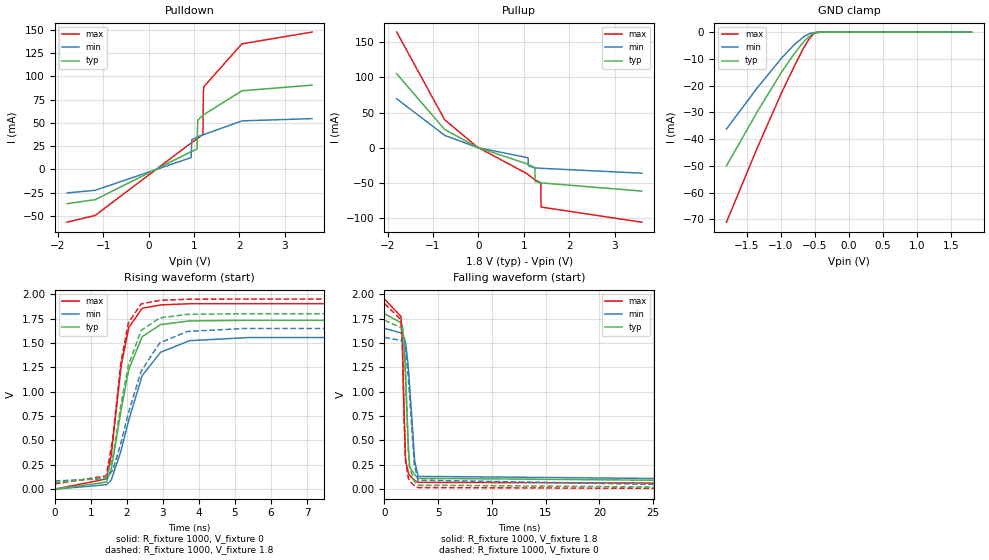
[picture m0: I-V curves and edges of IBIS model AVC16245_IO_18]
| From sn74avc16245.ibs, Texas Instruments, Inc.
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[Model]   AVC16245_IO_18
Model_type  I/O
Vinl = 0.5775
Vinh = 1.2675
Enable   Active-Low
Vref =   0
Rref =   1000
Cref =   30p
Vmeas =   0.9
| variable   typ   min   max
C_comp   7.10pF   6.11pF   8.84pF
| C_pullup   6.44pF   0.63pF   15.68pF
| C_pulldown   10.79pF   1.08pF   31.52pF
| C_tri-state   7.10pF   6.11pF   8.84pF
[Temperature Range]   40   100   -40
| Ambient temperature   25   85   -40
[Voltage range]   1.8   1.65   1.95
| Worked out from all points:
|   slope of the pulldown table from 0 to 0.27 V, typ, clamps not added: 41.9 ohm
|   slope of the pullup table from 0 to 0.27 V, typ, clamps not added: 42.5 ohm
|   GND clamp passes 1 mA (typ) near -0.56 V on its own axis
|   rising waveform, R_fixture 1000, V_fixture 0: 20-80 % time 546ps typ, 776ps min, 386ps max; typ from 0 V to 1.73 V
|   falling waveform, R_fixture 1000, V_fixture 1.8: 20-80 % time 373ps typ, 574ps min, 266ps max; typ from 1.8 V to 0.069 V
|   rising waveform, R_fixture 1000, V_fixture 1.8: 20-80 % time 533ps typ, 776ps min, 372ps max; typ from 0.069 V to 1.8 V
|   falling waveform, R_fixture 1000, V_fixture 0: 20-80 % time 381ps typ, 577ps min, 265ps max; typ from 1.73 V to 0 V
[GND Clamp]
| AVC16245_IO_18
|   Voltage   I(typ)   I(min)   I(max)
-1.8V     -50mA      -36.21mA   -71.03mA
-1.345V   -29.67mA   -20.75mA   -43.13mA
-985mV    -14.75mA   -9.574mA   -22.4mA
-805mV    -8.087mA   -4.753mA   -12.84mA
-665mV    -3.636mA   -1.756mA   -5.869mA
-585mV    -1.602mA   -602.7uA   -2.54mA
-520mV    -453.3uA   -219.6uA   -701.3uA
-480mV    -166.9uA   -118.3uA   -185.6uA
-390mV    -15.74uA   -24.31uA   -8.777uA
1.8V      678pA      10.87nA    27.01pA
[Pulldown]
| AVC16245_IO_18
|   Voltage   I(typ)   I(min)   I(max)
-1.8V     -36.68mA   -25.15mA   -56.6mA
-1.18V    -32.39mA   -22.35mA   -49.36mA
935mV     19.2mA     12.8mA     28.47mA
950mV     19.51mA    32.18mA    28.96mA
1.065V    21.97mA    34.85mA    32.96mA
1.08V     53.02mA    35.16mA    33.5mA
1.19V     58.05mA    37.16mA    37.58mA
1.195V    58.25mA    37.24mA    38mA
1.205V    58.63mA    37.4mA     84.09mA
1.215V    59.01mA    37.55mA    89mA
2.055V    84.56mA    52.22mA    135mA
3.6V      90.64mA    54.68mA    147.6mA
[Pullup]
| AVC16245_IO_18
|   Voltage   I(typ)   I(min)   I(max)
-1.8V     105.3mA    69.66mA    164.6mA
-745mV    26.07mA    17.69mA    39.91mA
-20mV     534.9uA    353.3uA    842.4uA
1.07V     -22.86mA   -13.96mA   -36.9mA
1.095V    -23.71mA   -14.56mA   -38.15mA
1.1V      -23.88mA   -25.5mA    -38.4mA
1.245V    -28.18mA   -28.58mA   -45.71mA
1.25V     -47.9mA    -28.62mA   -45.92mA
1.37V     -49.83mA   -29.18mA   -49.51mA
1.375V    -49.89mA   -29.19mA   -51.04mA
1.38V     -49.95mA   -29.21mA   -84.35mA
3.6V      -61.62mA   -36.17mA   -105.9mA
[Ramp]
| AVC16245_IO_18
| variable   typ   min   max
dV/dt_r   1.04/5.49E-10   0.93/7.79E-10   1.14/3.93E-10
dV/dt_f   1.04/3.82E-10   0.94/5.80E-10   1.14/2.71E-10
R_load = 1000
[Rising Waveform]
| AVC16245_IO_18
R_fixture =   1000
C_fixture =   0
L_fixture =   0
V_fixture =   0
V_fixture_min = 0
V_fixture_max = 0
|   Time   V(typ)   V(min)   V(max)
0s        26.34nV    128.4nV    946.4pV
1.43ns    72.24mV    45.45mV    104.8mV
1.565ns   201.5mV    91.95mV    346mV
1.845ns   823.1mV    403.3mV    1.274V
2.055ns   1.229V     711.5mV    1.659V
2.425ns   1.564V     1.164V     1.855V
2.935ns   1.688V     1.404V     1.89V
3.74ns    1.726V     1.523V     1.902V
5.365ns   1.732V     1.555V     1.903V
50ns      1.733V     1.556V     1.904V
[Falling Waveform]
| AVC16245_IO_18
R_fixture =   1000
C_fixture =   0
L_fixture =   0
V_fixture =   1.8
V_fixture_min = 1.65
V_fixture_max = 1.95
|   Time   V(typ)   V(min)   V(max)
0s        1.8V       1.65V      1.95V
1.53ns    1.707V     1.602V     1.772V
1.665ns   1.672V     1.583V     1.505V
1.82ns    1.528V     1.553V     794.7mV
1.97ns    1.166V     1.504V     287.2mV
2.21ns    464.7mV    1.26V      171.3mV
2.345ns   230.2mV    1.058V     138.7mV
2.81ns    147.7mV    289.7mV    88.5mV
3.135ns   111.6mV    131.5mV    70.35mV
50ns      68.88mV    84.87mV    53.71mV
[Rising Waveform]
| AVC16245_IO_18
R_fixture =   1000
C_fixture =   0
L_fixture =   0
V_fixture =   1.8
V_fixture_min = 1.65
V_fixture_max = 1.95
|   Time   V(typ)   V(min)   V(max)
0s        68.89mV    84.88mV    53.71mV
1.43ns    118.1mV    107.9mV    136.8mV
1.61ns    332.2mV    196.9mV    526.4mV
1.83ns    852.5mV    464.1mV    1.287V
2.04ns    1.265V     778mV      1.704V
2.395ns   1.628V     1.21V      1.9V
2.915ns   1.757V     1.501V     1.937V
3.68ns    1.793V     1.618V     1.948V
5.25ns    1.8V       1.648V     1.95V
50ns      1.8V       1.65V      1.95V
[Falling Waveform]
| AVC16245_IO_18
R_fixture =   1000
C_fixture =   0
L_fixture =   0
V_fixture =   0
V_fixture_min = 0
V_fixture_max = 0
|   Time   V(typ)   V(min)   V(max)
0s        1.733V     1.556V     1.904V
1.53ns    1.658V     1.526V     1.738V
1.665ns   1.621V     1.511V     1.462V
1.81ns    1.479V     1.483V     789.5mV
1.935ns   1.181V     1.443V     317.3mV
2.21ns    401.4mV    1.155V     117.9mV
2.33ns    218.8mV    965.8mV    86.56mV
2.77ns    84.88mV    255.7mV    36.09mV
3.115ns   41.53mV    93.02mV    16.34mV
50ns      -3.217uV   -5.18uV    -1.292uV
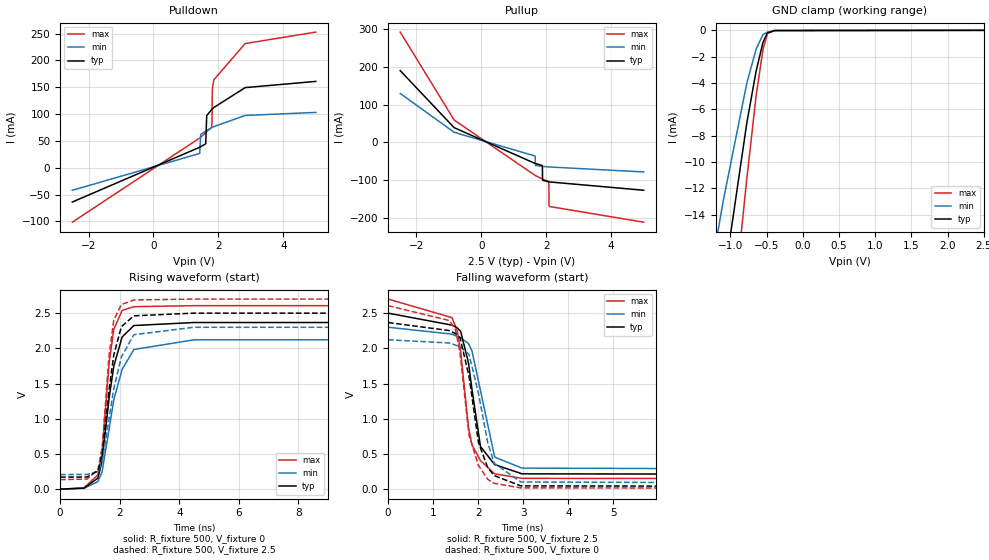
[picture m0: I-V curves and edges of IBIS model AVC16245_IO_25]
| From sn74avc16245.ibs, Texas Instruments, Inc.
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[Model]   AVC16245_IO_25
Model_type  I/O
Vinl = 0.7
Vinh = 1.7
Enable   Active-Low
Vref =   0
Rref =   500
Cref =   30p
Vmeas =   1.25
| variable   typ   min   max
C_comp   7.27pF   6.06pF   8.72pF
| C_pullup   8.12pF   1.36pF   24.55pF
| C_pulldown   13.49pF   4.14pF   37.98pF
| C_tri-state   7.27pF   6.06pF   8.72pF
[Temperature Range]   40   100   -40
| Ambient temperature   25   85   -40
[Voltage range]   2.5   2.3   2.7
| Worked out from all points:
|   slope of the pulldown table from 0 to 0.375 V, typ, clamps not added: 38 ohm
|   slope of the pullup table from 0 to 0.375 V, typ, clamps not added: 30.1 ohm
|   GND clamp passes 1 mA (typ) near -0.56 V on its own axis
|   rising waveform, R_fixture 500, V_fixture 0: 20-80 % time 442ps typ, 586ps min, 317ps max; typ from 0 V to 2.37 V
|   falling waveform, R_fixture 500, V_fixture 2.5: 20-80 % time 316ps typ, 382ps min, 297ps max; typ from 2.5 V to 0.172 V
|   rising waveform, R_fixture 500, V_fixture 2.5: 20-80 % time 408ps typ, 548ps min, 292ps max; typ from 0.172 V to 2.5 V
|   falling waveform, R_fixture 500, V_fixture 0: 20-80 % time 360ps typ, 413ps min, 332ps max; typ from 2.37 V to 0 V
[GND Clamp]
| AVC16245_IO_25
|   Voltage   I(typ)   I(min)   I(max)
-2.5V     -82.68mA   -61.21mA   -115.7mA
-1.605V   -41.15mA   -29.47mA   -58.91mA
-1.57V    -39.59mA   -28.28mA   -56.76mA
-1.335V   -29.24mA   -20.43mA   -42.53mA
-1.12V    -20.16mA   -13.59mA   -29.97mA
-1.09V    -18.93mA   -12.68mA   -28.26mA
-775mV    -7.064mA   -4.038mA   -11.31mA
-645mV    -3.082mA   -1.417mA   -4.956mA
-550mV    -906.2uA   -316.5uA   -1.425mA
-490mV    -194.4uA   -138.3uA   -256.2uA
-390mV    -15.74uA   -24.31uA   -8.777uA
2.5V      694pA      11.26nA    34.86pA
[Pulldown]
| AVC16245_IO_25
|   Voltage   I(typ)   I(min)   I(max)
-2.5V     -63.8mA    -41.97mA   -101.4mA
1.425V    38.28mA    26.72mA    55.55mA
1.455V    39.31mA    62.2mA     57.13mA
1.61V     44.68mA    68.36mA    65.45mA
1.64V     97.05mA    69.45mA    67.09mA
1.79V     108.4mA    74.59mA    75.18mA
1.805V    109.2mA    75.07mA    87.38mA
1.81V     109.5mA    75.23mA    135.9mA
1.815V    109.8mA    75.39mA    146.9mA
1.86V     112.3mA    76.79mA    164mA
2.825V    149.4mA    97.5mA     231.5mA
5V        161mA      103.2mA    252.9mA
[Pullup]
| AVC16245_IO_25
|   Voltage   I(typ)   I(min)   I(max)
-2.5V     190.4mA    129.9mA    292.8mA
-840mV    39.17mA    26.85mA    59.4mA
1.655V    -55.88mA   -36.16mA   -87.56mA
1.67V     -56.28mA   -61.22mA   -88.29mA
1.87V     -61mA      -63.63mA   -96.99mA
1.88V     -64.1mA    -63.73mA   -97.38mA
1.885V    -100.3mA   -63.77mA   -97.57mA
2.07V     -104.5mA   -65.1mA    -104.2mA
2.08V     -104.6mA   -65.15mA   -111.2mA
2.085V    -104.7mA   -65.17mA   -166.9mA
2.095V    -104.9mA   -65.22mA   -170.1mA
5V        -127mA     -78.45mA   -211.8mA
[Ramp]
| AVC16245_IO_25
| variable   typ   min   max
dV/dt_r   1.42/4.44E-10   1.27/5.92E-10   1.56/3.24E-10
dV/dt_f   1.40/3.28E-10   1.26/3.88E-10   1.54/3.15E-10
R_load = 500
[Rising Waveform]
| AVC16245_IO_25
R_fixture =   500
C_fixture =   0
L_fixture =   0
V_fixture =   0
V_fixture_min = 0
V_fixture_max = 0
|   Time   V(typ)   V(min)   V(max)
0s        31.64nV    130.9nV    1.42nV
800ps     14.56mV    12.53mV    18.91mV
1.265ns   155.9mV    106.1mV    202.9mV
1.405ns   391.7mV    241.4mV    507.1mV
1.645ns   1.298V     855mV      1.793V
1.8ns     1.744V     1.268V     2.269V
2.08ns    2.161V     1.701V     2.538V
2.475ns   2.324V     1.984V     2.592V
4.495ns   2.367V     2.121V     2.606V
50ns      2.367V     2.122V     2.606V
[Falling Waveform]
| AVC16245_IO_25
R_fixture =   500
C_fixture =   0
L_fixture =   0
V_fixture =   2.5
V_fixture_min = 2.3
V_fixture_max = 2.7
|   Time   V(typ)   V(min)   V(max)
0s        2.5V       2.3V       2.7V
1.415ns   2.33V      2.202V     2.437V
1.53ns    2.293V     2.17V      2.261V
1.61ns    2.242V     2.149V     1.956V
1.785ns   1.791V     2.068V     872.3mV
1.86ns    1.423V     1.966V     632.8mV
2.05ns    605.4mV    1.4V       405.5mV
2.365ns   349.1mV    455.5mV    217.7mV
2.97ns    217.9mV    299mV      153.6mV
50ns      171.7mV    207.2mV    135.8mV
[Rising Waveform]
| AVC16245_IO_25
R_fixture =   500
C_fixture =   0
L_fixture =   0
V_fixture =   2.5
V_fixture_min = 2.3
V_fixture_max = 2.7
|   Time   V(typ)   V(min)   V(max)
0s        171.7mV    207.2mV    135.8mV
905ps     172.4mV    209.2mV    142.8mV
1.275ns   264mV      249.5mV    283.2mV
1.415ns   519.4mV    402.1mV    607.3mV
1.64ns    1.404V     997.4mV    1.887V
1.8ns     1.905V     1.427V     2.401V
2.055ns   2.308V     1.877V     2.622V
2.475ns   2.462V     2.194V     2.687V
4.485ns   2.5V       2.299V     2.7V
50ns      2.5V       2.3V       2.7V
[Falling Waveform]
| AVC16245_IO_25
R_fixture =   500
C_fixture =   0
L_fixture =   0
V_fixture =   0
V_fixture_min = 0
V_fixture_max = 0
|   Time   V(typ)   V(min)   V(max)
0s        2.367V     2.122V     2.606V
1.36ns    2.252V     2.076V     2.395V
1.495ns   2.209V     2.047V     2.266V
1.595ns   2.154V     2.021V     1.941V
1.795ns   1.605V     1.915V     771.2mV
2.005ns   663.7mV    1.363V     338mV
2.21ns    306mV      662.4mV    141.4mV
2.355ns   192.7mV    367.7mV    82.2mV
2.945ns   46.35mV    102mV      18.29mV
50ns      -2.825uV   -4.479uV   -1.118uV
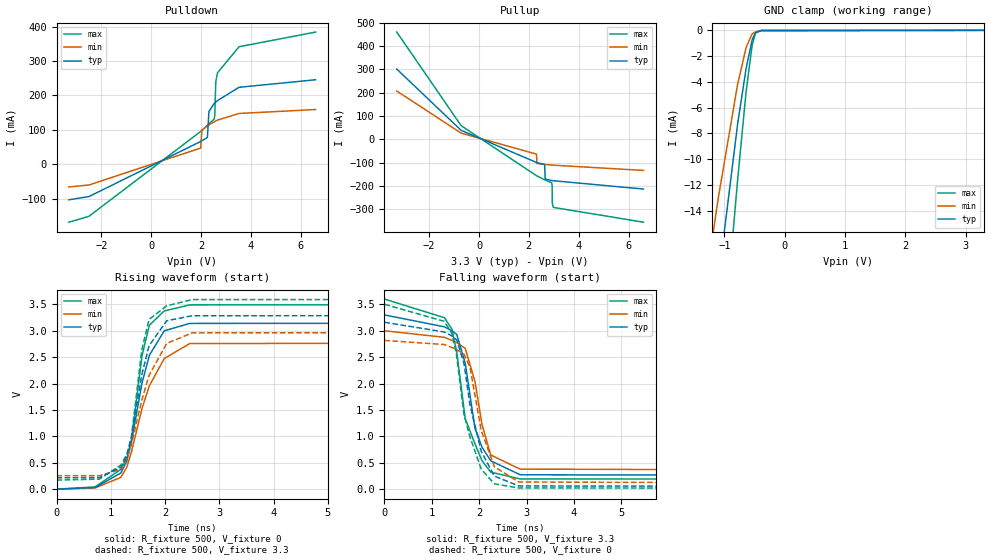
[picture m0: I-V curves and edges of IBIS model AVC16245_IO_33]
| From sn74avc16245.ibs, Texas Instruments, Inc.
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[Model]   AVC16245_IO_33
Model_type  I/O
Vinl = 0.8
Vinh = 2.0
Enable   Active-Low
Vref =   0
Rref =   500
Cref =   30p
Vmeas =   1.65
| variable   typ   min   max
C_comp   7.39pF   5.99pF   8.69pF
| C_pullup   10.17pF   4.51pF   30.54pF
| C_pulldown   14.91pF   5.29pF   42.01pF
| C_tri-state   7.39pF   5.99pF   8.69pF
[Temperature Range]   40   100   -40
| Ambient temperature   25   85   -40
[Voltage range]   3.3   3   3.6
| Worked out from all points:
|   slope of the pulldown table from 0 to 0.495 V, typ, clamps not added: 35.6 ohm
|   slope of the pullup table from 0 to 0.495 V, typ, clamps not added: 23.7 ohm
|   GND clamp passes 1 mA (typ) near -0.56 V on its own axis
|   rising waveform, R_fixture 500, V_fixture 0: 20-80 % time 383ps typ, 496ps min, 295ps max; typ from 0 V to 3.16 V
|   falling waveform, R_fixture 500, V_fixture 3.3: 20-80 % time 401ps typ, 351ps min, 452ps max; typ from 3.3 V to 0.215 V
|   rising waveform, R_fixture 500, V_fixture 3.3: 20-80 % time 344ps typ, 454ps min, 266ps max; typ from 0.215 V to 3.3 V
|   falling waveform, R_fixture 500, V_fixture 0: 20-80 % time 434ps typ, 403ps min, 441ps max; typ from 3.16 V to 0 V
[GND Clamp]
| AVC16245_IO_33
|   Voltage   I(typ)   I(min)   I(max)
-3.3V     -121mA     -90.61mA   -168.1mA
-1.61V    -41.38mA   -29.65mA   -59.22mA
-1.36V    -30.32mA   -21.25mA   -44.02mA
-1.32V    -28.59mA   -19.94mA   -41.64mA
-1.13V    -20.57mA   -13.9mA    -30.54mA
-1.095V   -19.14mA   -12.83mA   -28.54mA
-780mV    -7.233mA   -4.155mA   -11.56mA
-640mV    -2.948mA   -1.337mA   -4.735mA
-540mV    -738uA     -268.9uA   -1.157mA
-485mV    -176.3uA   -127.9uA   -215.4uA
-390mV    -15.74uA   -24.32uA   -8.777uA
3.3V      718.9pA    11.01nA    43.35pA
[Pulldown]
| AVC16245_IO_33
|   Voltage   I(typ)   I(min)   I(max)
-3.3V     -103.6mA   -66.37mA   -168.8mA
-2.495V   -94.32mA   -60.65mA   -151.7mA
1.99V     66mA       46.86mA    95.14mA
2.035V    67.99mA    97.91mA    98.11mA
2.26V     77.74mA    111.8mA    113.1mA
2.32V     153mA      114.4mA    117.2mA
2.53V     176.3mA    123.1mA    130.9mA
2.555V    177.9mA    124.1mA    140.5mA
2.595V    180.5mA    125.6mA    239.6mA
2.665V    184.9mA    128.2mA    265.7mA
3.53V     223.5mA    147.4mA    341.5mA
6.6V      245.5mA    158.9mA    384.1mA
[Pullup]
| AVC16245_IO_33
|   Voltage   I(typ)   I(min)   I(max)
-3.3V     300.9mA    206.8mA    459.7mA
-720mV    38.25mA    26.26mA    58.45mA
2.305V    -99.64mA   -63.89mA   -156.4mA
2.33V     -100.4mA   -104.2mA   -157.8mA
2.625V    -108.2mA   -108.4mA   -173.8mA
2.635V    -111mA     -108.5mA   -174.3mA
2.655V    -170.7mA   -108.7mA   -175.2mA
2.92V     -177.2mA   -111mA     -187.2mA
2.935V    -177.5mA   -111.1mA   -200.8mA
2.94V     -177.6mA   -111.1mA   -272.9mA
2.98V     -178.2mA   -111.4mA   -292.6mA
6.6V      -213.9mA   -134mA     -356.1mA
[Ramp]
| AVC16245_IO_33
| variable   typ   min   max
dV/dt_r   1.90/3.85E-10   1.69/5.00E-10   2.10/2.98E-10
dV/dt_f   1.85/4.06E-10   1.65/3.57E-10   2.06/4.58E-10
R_load = 500
[Rising Waveform]
| AVC16245_IO_33
R_fixture =   500
C_fixture =   0
L_fixture =   0
V_fixture =   0
V_fixture_min = 0
V_fixture_max = 0
|   Time   V(typ)   V(min)   V(max)
0s        42.31nV    147.8nV    2.423nV
710ps     31.43mV    22.94mV    42.36mV
1.185ns   306.8mV    223.2mV    374.4mV
1.295ns   535.1mV    417.9mV    596.7mV
1.38ns    891.5mV    704.3mV    929.5mV
1.575ns   2.011V     1.528V     2.53V
1.71ns    2.535V     1.958V     3.103V
1.985ns   2.999V     2.474V     3.376V
2.455ns   3.139V     2.758V     3.49V
50ns      3.161V     2.817V     3.501V
[Falling Waveform]
| AVC16245_IO_33
R_fixture =   500
C_fixture =   0
L_fixture =   0
V_fixture =   3.3
V_fixture_min = 3
V_fixture_max = 3.6
|   Time   V(typ)   V(min)   V(max)
0s        3.3V       3V         3.6V
1.265ns   3.074V     2.876V     3.247V
1.425ns   3.001V     2.816V     3.029V
1.525ns   2.932V     2.775V     2.611V
1.705ns   2.39V      2.669V     1.337V
1.91ns    1.158V     2.045V     861.2mV
2.06ns    793.8mV    1.225V     539.4mV
2.245ns   537.4mV    646.3mV    321.9mV
2.865ns   272.3mV    379.9mV    193.8mV
50ns      214.5mV    254.5mV    171.8mV
[Rising Waveform]
| AVC16245_IO_33
R_fixture =   500
C_fixture =   0
L_fixture =   0
V_fixture =   3.3
V_fixture_min = 3
V_fixture_max = 3.6
|   Time   V(typ)   V(min)   V(max)
0s        214.5mV    254.5mV    171.8mV
790ps     218.9mV    255.7mV    190mV
1.19ns    419.7mV    374.3mV    459.8mV
1.3ns     642.9mV    573.9mV    674mV
1.38ns    984.4mV    848.7mV    992.1mV
1.57ns    2.166V     1.68V      2.632V
1.705ns   2.716V     2.157V     3.215V
2.03ns    3.19V      2.76V      3.472V
2.5ns     3.284V     2.96V      3.59V
50ns      3.3V       3V         3.6V
[Falling Waveform]
| AVC16245_IO_33
R_fixture =   500
C_fixture =   0
L_fixture =   0
V_fixture =   0
V_fixture_min = 0
V_fixture_max = 0
|   Time   V(typ)   V(min)   V(max)
0s        3.161V     2.817V     3.501V
1.26ns    2.977V     2.739V     3.179V
1.425ns   2.902V     2.682V     2.953V
1.525ns   2.829V     2.642V     2.523V
1.68ns    2.378V     2.555V     1.41V
1.805ns   1.599V     2.315V     991.8mV
2.045ns   712.8mV    1.106V     375.3mV
2.32ns    248.3mV    425.5mV    101.7mV
2.835ns   61mV       135.7mV    22.96mV
50ns      -2.905uV   -4.245uV   -1.282uV
